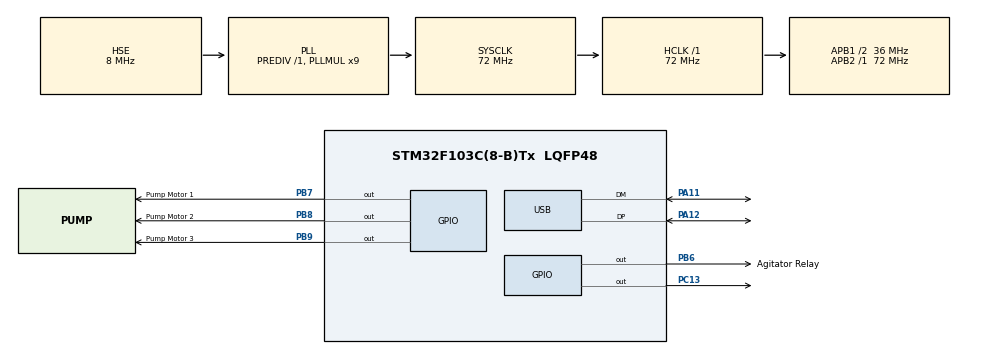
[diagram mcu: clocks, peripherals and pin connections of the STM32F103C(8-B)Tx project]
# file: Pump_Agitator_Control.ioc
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Mcu.Family=STM32F1
Mcu.Name=STM32F103C(8-B)Tx
Mcu.Package=LQFP48
NVIC.PriorityGroup=NVIC_PRIORITYGROUP_4
NVIC.USB_LP_CAN1_RX0_IRQn=true\:0\:0\:false\:false\:true\:false\:true\:true
PA11.Mode=Device
PA11.Signal=USB_DM
PA12.Mode=Device
PA12.Signal=USB_DP
PA13.Mode=Serial_Wire
PA13.Signal=SYS_JTMS-SWDIO
PA14.Mode=Serial_Wire
PA14.Signal=SYS_JTCK-SWCLK
PB6.GPIO_Label=Agitator Relay
PB6.Signal=GPIO_Output
PB7.GPIO_Label=Pump Motor 1
PB7.Signal=GPIO_Output
PB8.GPIO_Label=Pump Motor 2
PB8.Signal=GPIO_Output
PB9.GPIO_Label=Pump Motor 3
PB9.Signal=GPIO_Output
PC13-TAMPER-RTC.Signal=GPIO_Output
PD0-OSC_IN.Mode=HSE-External-Oscillator
PD0-OSC_IN.Signal=RCC_OSC_IN
PD1-OSC_OUT.Mode=HSE-External-Oscillator
PD1-OSC_OUT.Signal=RCC_OSC_OUT
ProjectManager.HeapSize=0x200
ProjectManager.StackSize=0x400
ProjectManager.TargetToolchain=CMake
RCC.AHBFreq_Value=72000000
RCC.APB1CLKDivider=RCC_HCLK_DIV2
RCC.APB1Freq_Value=36000000
RCC.APB1TimFreq_Value=72000000
RCC.APB2Freq_Value=72000000
RCC.APB2TimFreq_Value=72000000
RCC.HCLKFreq_Value=72000000
RCC.PLLMUL=RCC_PLL_MUL9
RCC.SYSCLKFreq_VALUE=72000000
RCC.SYSCLKSource=RCC_SYSCLKSOURCE_PLLCLK
RCC.USBFreq_Value=48000000
RCC.USBPrescaler=RCC_USBCLKSOURCE_PLL_DIV1_5
USB_DEVICE.CLASS_NAME_FS=CDC
USB_DEVICE.VirtualMode=Cdc
USB_DEVICE.VirtualModeFS=Cdc_FS
VP_USB_DEVICE_VS_USB_DEVICE_CDC_FS.Mode=CDC_FS
board=custom

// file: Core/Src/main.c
/* USER CODE BEGIN Header */
/**
 ******************************************************************************
 * @file           : main.c
 * @brief          : Main program body
 ******************************************************************************
 * @attention
 *
 * Copyright (c) 2025 STMicroelectronics.
 * All rights reserved.
 *
 * This software is licensed under terms that can be found in the LICENSE file
 * in the root directory of this software component.
 * If no LICENSE file comes with this software, it is provided AS-IS.
 *
 ******************************************************************************
 */
/* USER CODE END Header */
#include "main.h"
#include "usb_device.h"

/* USER CODE BEGIN Includes */
#include "agitator_control.h"
#include "comm_handler.h"
#include "pump_control.h"
#include "system_command.h"

/* USER CODE END Includes */

void SystemClock_Config(void);
static void MX_GPIO_Init(void);

int main(void) {

  /* MCU Configuration--------------------------------------------------------*/

  /* Reset of all peripherals, Initializes the Flash interface and the Systick.
   */
  HAL_Init();

  /* Configure the system clock */
  SystemClock_Config();

  /* Initialize all configured peripherals */
  MX_GPIO_Init();
  MX_USB_DEVICE_Init();
  /* USER CODE BEGIN 2 */
  comm_init();
  pump_init();
  agitator_init();
  // system_init();

  /* USER CODE END 2 */

  /* Infinite loop */
  while (1) {
    comm_process_frames();
    pump_task();
    agitator_task();
   // HAL_Delay(10);
  }
}

void SystemClock_Config(void) {
  RCC_OscInitTypeDef RCC_OscInitStruct = {0};
  RCC_ClkInitTypeDef RCC_ClkInitStruct = {0};
  RCC_PeriphCLKInitTypeDef PeriphClkInit = {0};

  /** Initializes the RCC Oscillators according to the specified parameters
   * in the RCC_OscInitTypeDef structure.
   */
  RCC_OscInitStruct.OscillatorType = RCC_OSCILLATORTYPE_HSE;
  RCC_OscInitStruct.HSEState = RCC_HSE_ON;
  RCC_OscInitStruct.HSEPredivValue = RCC_HSE_PREDIV_DIV1;
  RCC_OscInitStruct.HSIState = RCC_HSI_ON;
  RCC_OscInitStruct.PLL.PLLState = RCC_PLL_ON;
  RCC_OscInitStruct.PLL.PLLSource = RCC_PLLSOURCE_HSE;
  RCC_OscInitStruct.PLL.PLLMUL = RCC_PLL_MUL9;
  if (HAL_RCC_OscConfig(&RCC_OscInitStruct) != HAL_OK) {
    Error_Handler();
  }

  /** Initializes the CPU, AHB and APB buses clocks
   */
  RCC_ClkInitStruct.ClockType = RCC_CLOCKTYPE_HCLK | RCC_CLOCKTYPE_SYSCLK |
                                RCC_CLOCKTYPE_PCLK1 | RCC_CLOCKTYPE_PCLK2;
  RCC_ClkInitStruct.SYSCLKSource = RCC_SYSCLKSOURCE_PLLCLK;
  RCC_ClkInitStruct.AHBCLKDivider = RCC_SYSCLK_DIV1;
  RCC_ClkInitStruct.APB1CLKDivider = RCC_HCLK_DIV2;
  RCC_ClkInitStruct.APB2CLKDivider = RCC_HCLK_DIV1;

  if (HAL_RCC_ClockConfig(&RCC_ClkInitStruct, FLASH_LATENCY_2) != HAL_OK) {
    Error_Handler();
  }
  PeriphClkInit.PeriphClockSelection = RCC_PERIPHCLK_USB;
  PeriphClkInit.UsbClockSelection = RCC_USBCLKSOURCE_PLL_DIV1_5;
  if (HAL_RCCEx_PeriphCLKConfig(&PeriphClkInit) != HAL_OK) {
    Error_Handler();
  }
}

static void MX_GPIO_Init(void) {
  GPIO_InitTypeDef GPIO_InitStruct = {0};

  /* GPIO Ports Clock Enable */
  __HAL_RCC_GPIOC_CLK_ENABLE();
  __HAL_RCC_GPIOD_CLK_ENABLE();
  __HAL_RCC_GPIOA_CLK_ENABLE();
  __HAL_RCC_GPIOB_CLK_ENABLE();

  /*Configure GPIO pin Output Level */
  HAL_GPIO_WritePin(GPIOC, GPIO_PIN_13, GPIO_PIN_RESET);

  /*Configure GPIO pin Output Level */
  HAL_GPIO_WritePin(GPIOB,
                    Agitator_Relay_Pin | Pump_Motor_1_Pin | Pump_Motor_2_Pin |
                        Pump_Motor_3_Pin,
                    GPIO_PIN_RESET);

  /*Configure GPIO pin : PC13 */
  GPIO_InitStruct.Pin = GPIO_PIN_13;
  GPIO_InitStruct.Mode = GPIO_MODE_OUTPUT_PP;
  GPIO_InitStruct.Pull = GPIO_NOPULL;
  GPIO_InitStruct.Speed = GPIO_SPEED_FREQ_LOW;
  HAL_GPIO_Init(GPIOC, &GPIO_InitStruct);

  /*Configure GPIO pins : Agitator_Relay_Pin Pump_Motor_1_Pin Pump_Motor_2_Pin
   * Pump_Motor_3_Pin */
  GPIO_InitStruct.Pin = Agitator_Relay_Pin | Pump_Motor_1_Pin |
                        Pump_Motor_2_Pin | Pump_Motor_3_Pin | Pump_Motor_4_Pin | Pump_Motor_5_Pin |
                        Pump_Motor_6_Pin;
  GPIO_InitStruct.Mode = GPIO_MODE_OUTPUT_PP;
  GPIO_InitStruct.Pull = GPIO_NOPULL;
  GPIO_InitStruct.Speed = GPIO_SPEED_FREQ_LOW;
  HAL_GPIO_Init(GPIOB, &GPIO_InitStruct);

}

void Error_Handler(void) {
  __disable_irq();
  while (1) {
  }
}
#ifdef USE_FULL_ASSERT
/**
 * @brief  Reports the name of the source file and the source line number
 *         where the assert_param error has occurred.
 * @param  file: pointer to the source file name
 * @param  line: assert_param error line source number
 * @retval None
 */
void assert_failed(uint8_t *file, uint32_t line) {
  /* USER CODE BEGIN 6 */
  /* User can add his own implementation to report the file name and line
     number, ex: printf("Wrong parameters value: file %s on line %d\r\n", file,
     line) */
  /* USER CODE END 6 */
}
#endif /* USE_FULL_ASSERT */
